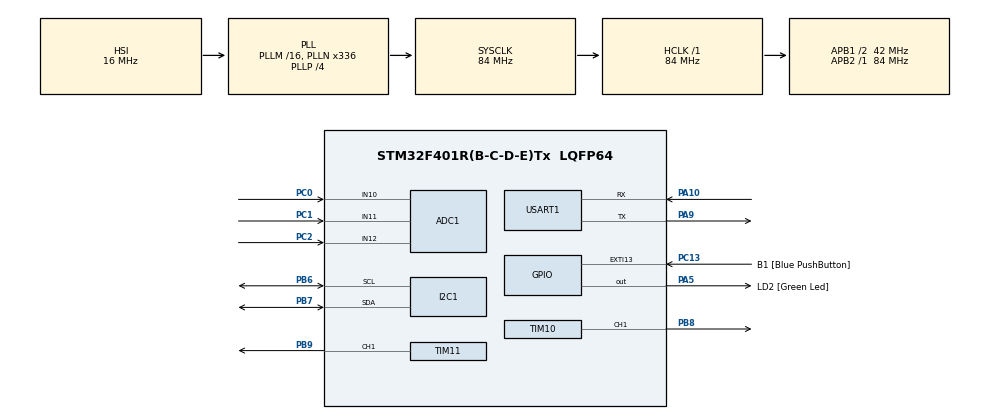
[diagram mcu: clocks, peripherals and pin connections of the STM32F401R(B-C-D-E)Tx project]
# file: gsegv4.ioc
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ADC1.Channel=ADC_CHANNEL_11
ADC1.Channel-0\#ChannelRegularConversion=ADC_CHANNEL_10
ADC1.Channel-1\#ChannelRegularConversion=ADC_CHANNEL_11
ADC1.Channel-2\#ChannelRegularConversion=ADC_CHANNEL_12
ADC1.ClockPrescaler=ADC_CLOCKPRESCALER_PCLK_DIV8
ADC1.ContinuousConvMode=ENABLE
ADC1.DMAContinuousRequests=ENABLE
ADC1.EOCSelection=EOC_SINGLE_CONV
ADC1.NbrOfConversion=3
ADC1.NbrOfConversionFlag=1
ADC1.Rank-1\#ChannelRegularConversion=2
ADC1.Rank-2\#ChannelRegularConversion=3
ADC1.ScanConvMode=ENABLE
ADC1.master=1
Dma.ADC1.0.Channel=DMA_CHANNEL_0
Dma.ADC1.0.Direction=DMA_PERIPH_TO_MEMORY
Dma.ADC1.0.FIFOMode=DMA_FIFOMODE_DISABLE
Dma.ADC1.0.Instance=DMA2_Stream0
Dma.ADC1.0.MemDataAlignment=DMA_MDATAALIGN_WORD
Dma.ADC1.0.MemInc=DMA_MINC_ENABLE
Dma.ADC1.0.Mode=DMA_CIRCULAR
Dma.ADC1.0.PeriphDataAlignment=DMA_PDATAALIGN_WORD
Dma.ADC1.0.PeriphInc=DMA_PINC_DISABLE
Dma.ADC1.0.Priority=DMA_PRIORITY_LOW
Dma.Request0=ADC1
FREERTOS.Tasks01=defaultTask,0,128,StartDefaultTask
Mcu.Family=STM32F4
Mcu.Name=STM32F401R(B-C-D-E)Tx
Mcu.Package=LQFP64
NVIC.PriorityGroup=NVIC_PRIORITYGROUP_4
NVIC.USART1_IRQn=true\:5\:0\:false
PA10.Mode=Asynchronous
PA10.Signal=USART1_RX
PA13.GPIO_Label=TMS
PA13.Mode=Trace-Asynchronous_SW
PA13.Signal=SYS_JTMS-SWDIO
PA14.GPIO_Label=TCK
PA14.Mode=Trace-Asynchronous_SW
PA14.Signal=SYS_JTCK-SWCLK
PA2.GPIO_Label=USART_TX
PA2.GPIO_Mode=GPIO_MODE_AF_PP
PA2.GPIO_PuPd=GPIO_NOPULL
PA2.GPIO_Speed=GPIO_SPEED_LOW
PA2.Signal=USART2_TX
PA3.GPIO_Label=USART_RX
PA3.GPIO_Mode=GPIO_MODE_AF_PP
PA3.GPIO_PuPd=GPIO_NOPULL
PA3.GPIO_Speed=GPIO_SPEED_LOW
PA3.Signal=USART2_RX
PA5.GPIO_Label=LD2 [Green Led]
PA5.GPIO_Mode=GPIO_MODE_OUTPUT_PP
PA5.GPIO_ModeDefaultOutputPP=GPIO_MODE_OUTPUT_PP
PA5.GPIO_PuPd=GPIO_NOPULL
PA5.GPIO_Speed=GPIO_SPEED_LOW
PA5.Signal=GPIO_Output
PA9.Mode=Asynchronous
PA9.Signal=USART1_TX
PB3.GPIO_Label=SWO
PB3.Mode=Trace-Asynchronous_SW
PB3.Signal=SYS_JTDO-SWO
PB6.Mode=I2C
PB6.Signal=I2C1_SCL
PB7.Mode=I2C
PB7.Signal=I2C1_SDA
PB8.Signal=S_TIM10_CH1
PB9.Signal=S_TIM11_CH1
PC0.Signal=ADCx_IN10
PC1.Signal=ADCx_IN11
PC13-ANTI_TAMP.GPIO_Label=B1 [Blue PushButton]
PC13-ANTI_TAMP.GPIO_ModeDefaultEXTI=GPIO_MODE_EVT_RISING
PC13-ANTI_TAMP.GPIO_PuPd=GPIO_NOPULL
PC13-ANTI_TAMP.Signal=GPXTI13
PC14-OSC32_IN.Signal=RCC_OSC32_IN
PC15-OSC32_OUT.Signal=RCC_OSC32_OUT
PC2.Signal=ADCx_IN12
PH0\ -\ OSC_IN.Signal=RCC_OSC_IN
PH1\ -\ OSC_OUT.Signal=RCC_OSC_OUT
ProjectManager.TargetToolchain=MDK-ARM 4.73
RCC.48MHZClocksFreq_Value=48000000
RCC.AHBFreq_Value=84000000
RCC.APB1CLKDivider=RCC_HCLK_DIV2
RCC.APB1Freq_Value=42000000
RCC.APB1TimFreq_Value=84000000
RCC.APB2Freq_Value=84000000
RCC.APB2TimFreq_Value=84000000
RCC.CortexFreq_Value=10500000
RCC.HCLKFreq_Value=84000000
RCC.HSE_VALUE=8000000
RCC.HSI_VALUE=16000000
RCC.LSE_VALUE=32768
RCC.PLLN=336
RCC.PLLP=RCC_PLLP_DIV4
RCC.PLLQ=7
RCC.SYSCLKFreq_VALUE=84000000
RCC.SYSCLKSource=RCC_SYSCLKSOURCE_PLLCLK
RCC.VCOOutputFreq_Value=336000000
SH.ADCx_IN10.0=ADC1_IN10,IN10
SH.ADCx_IN11.0=ADC1_IN11,IN11
SH.ADCx_IN12.0=ADC1_IN12,IN12
SH.S_TIM10_CH1.0=TIM10_CH1,PWM Generation1 CH1
SH.S_TIM11_CH1.0=TIM11_CH1,PWM Generation1 CH1
VP_FREERTOS_VS_ENABLE.Mode=Enabled
VP_TIM10_VS_ClockSourceINT.Mode=Enable_Timer
VP_TIM11_VS_ClockSourceINT.Mode=Enable_Timer

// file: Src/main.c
/**
  ******************************************************************************
  * File Name          : main.c
  * Date               : 25/04/2015 11:45:40
  * Description        : Main program body
  ******************************************************************************
  *
  * COPYRIGHT(c) 2015 STMicroelectronics
  *
  * Redistribution and use in source and binary forms, with or without modification,
  * are permitted provided that the following conditions are met:
  *   1. Redistributions of source code must retain the above copyright notice,
  *      this list of conditions and the following disclaimer.
  *   2. Redistributions in binary form must reproduce the above copyright notice,
  *      this list of conditions and the following disclaimer in the documentation
  *      and/or other materials provided with the distribution.
  *   3. Neither the name of STMicroelectronics nor the names of its contributors
  *      may be used to endorse or promote products derived from this software
  *      without specific prior written permission.
  *
  * THIS SOFTWARE IS PROVIDED BY THE COPYRIGHT HOLDERS AND CONTRIBUTORS "AS IS"
  * AND ANY EXPRESS OR IMPLIED WARRANTIES, INCLUDING, BUT NOT LIMITED TO, THE
  * IMPLIED WARRANTIES OF MERCHANTABILITY AND FITNESS FOR A PARTICULAR PURPOSE ARE
  * DISCLAIMED. IN NO EVENT SHALL THE COPYRIGHT HOLDER OR CONTRIBUTORS BE LIABLE
  * FOR ANY DIRECT, INDIRECT, INCIDENTAL, SPECIAL, EXEMPLARY, OR CONSEQUENTIAL
  * DAMAGES (INCLUDING, BUT NOT LIMITED TO, PROCUREMENT OF SUBSTITUTE GOODS OR
  * SERVICES; LOSS OF USE, DATA, OR PROFITS; OR BUSINESS INTERRUPTION) HOWEVER
  * CAUSED AND ON ANY THEORY OF LIABILITY, WHETHER IN CONTRACT, STRICT LIABILITY,
  * OR TORT (INCLUDING NEGLIGENCE OR OTHERWISE) ARISING IN ANY WAY OUT OF THE USE
  * OF THIS SOFTWARE, EVEN IF ADVISED OF THE POSSIBILITY OF SUCH DAMAGE.
  *
  ******************************************************************************
  */

#include "stdio.h"
#include "stm32f4xx_hal.h"
#include "cmsis_os.h"
#include "FreeRTOS.h"                       // Primary header for FreeRTOS
#include "task.h"                           // Header for FreeRTOS task functions
#include "queue.h"                          // FreeRTOS inter-task communication queues
#include "croutine.h"                       // Header for co-routines and such
#include "semphr.h"

#include "shares.h"
#include "task_safety.h"
#include "task_master.h"
#include "task_control.h"
#include "task_test.h"

ADC_HandleTypeDef hadc1;
DMA_HandleTypeDef hdma_adc1;

I2C_HandleTypeDef hi2c1;

TIM_HandleTypeDef htim10;
TIM_HandleTypeDef htim11;

UART_HandleTypeDef huart1;

void SystemClock_Config(void);
static void MX_GPIO_Init(void);
static void MX_DMA_Init(void);
static void MX_ADC1_Init(void);
static void MX_I2C1_Init(void);
static void MX_TIM10_Init(void);
static void MX_TIM11_Init(void);
static void MX_USART1_UART_Init(void);
void StartDefaultTask(void const * argument);
#ifdef __GNUC__
  /* With GCC/RAISONANCE, small printf (option LD Linker->Libraries->Small printf
     set to 'Yes') calls __io_putchar() */
  #define PUTCHAR_PROTOTYPE int __io_putchar(int ch)
#else
  #define PUTCHAR_PROTOTYPE int fputc(int ch, FILE *f)
#endif /* __GNUC__ */
PUTCHAR_PROTOTYPE
{
  /* Place your implementation of fputc here */
  /* e.g. write a character to the EVAL_COM1 and Loop until the end of transmission */
  HAL_UART_Transmit(&huart1, (uint8_t *)&ch, 1, 0xFFFF);

  return ch;
}

xQueueHandle update_coefficients_QUEUE;
xSemaphoreHandle testing_SEMAPHORE;
xSemaphoreHandle data_SEMAPHORE;
xQueueHandle control_sig_QUEUE;
//vSemaphoreCreateBinary(testing_SEMAPHORE);

int main(void)
{

  /* Reset of all peripherals, Initializes the Flash interface and the Systick. */
  HAL_Init();

  /* Configure the system clock */
  SystemClock_Config();

  /* Initialize all configured peripherals */
  MX_GPIO_Init();
  MX_DMA_Init();
  MX_ADC1_Init();
  MX_I2C1_Init();
  MX_TIM10_Init();
  MX_TIM11_Init();
  MX_USART1_UART_Init();

  xTaskCreate(task_safety, "Safety", 350, NULL, 1, NULL);
  xTaskCreate(task_master, "Master", 350, NULL, 1, NULL);
  xTaskCreate(task_control, "Control", 1000, NULL, 3, NULL);
  xTaskCreate(task_test, "Test", 500, NULL, 4, NULL);

  update_coefficients_QUEUE = xQueueCreate(3, sizeof(uint8_t));
  control_sig_QUEUE = xQueueCreate(3, sizeof(int16_t));;
  vSemaphoreCreateBinary(testing_SEMAPHORE);
  vSemaphoreCreateBinary(data_SEMAPHORE);
  osKernelStart();

  /* We should never get here as control is now taken by the scheduler */
  /* Infinite loop */
  while (1)
  {

  }

}

/** System Clock Configuration
*/
void SystemClock_Config(void)
{

  RCC_OscInitTypeDef RCC_OscInitStruct;
  RCC_ClkInitTypeDef RCC_ClkInitStruct;

  __PWR_CLK_ENABLE();

  __HAL_PWR_VOLTAGESCALING_CONFIG(PWR_REGULATOR_VOLTAGE_SCALE2);

  RCC_OscInitStruct.OscillatorType = RCC_OSCILLATORTYPE_HSI;
  RCC_OscInitStruct.HSIState = RCC_HSI_ON;
  RCC_OscInitStruct.HSICalibrationValue = 6;
  RCC_OscInitStruct.PLL.PLLState = RCC_PLL_ON;
  RCC_OscInitStruct.PLL.PLLSource = RCC_PLLSOURCE_HSI;
  RCC_OscInitStruct.PLL.PLLM = 16;
  RCC_OscInitStruct.PLL.PLLN = 336;
  RCC_OscInitStruct.PLL.PLLP = RCC_PLLP_DIV4;
  RCC_OscInitStruct.PLL.PLLQ = 7;
  HAL_RCC_OscConfig(&RCC_OscInitStruct);

  RCC_ClkInitStruct.ClockType = RCC_CLOCKTYPE_SYSCLK|RCC_CLOCKTYPE_PCLK1;
  RCC_ClkInitStruct.SYSCLKSource = RCC_SYSCLKSOURCE_PLLCLK;
  RCC_ClkInitStruct.AHBCLKDivider = RCC_SYSCLK_DIV1;
  RCC_ClkInitStruct.APB1CLKDivider = RCC_HCLK_DIV2;
  RCC_ClkInitStruct.APB2CLKDivider = RCC_HCLK_DIV1;
  HAL_RCC_ClockConfig(&RCC_ClkInitStruct, FLASH_LATENCY_2);

}

/* ADC1 init function */
void MX_ADC1_Init(void)
{

  ADC_ChannelConfTypeDef sConfig;

    /**Configure the global features of the ADC (Clock, Resolution, Data Alignment and number of conversion)
    */
  hadc1.Instance = ADC1;
  hadc1.Init.ClockPrescaler = ADC_CLOCKPRESCALER_PCLK_DIV8;
  hadc1.Init.Resolution = ADC_RESOLUTION12b;
  hadc1.Init.ScanConvMode = ENABLE;
  hadc1.Init.ContinuousConvMode = ENABLE;
  hadc1.Init.DiscontinuousConvMode = DISABLE;
  hadc1.Init.ExternalTrigConvEdge = ADC_EXTERNALTRIGCONVEDGE_NONE;
  hadc1.Init.DataAlign = ADC_DATAALIGN_RIGHT;
  hadc1.Init.NbrOfConversion = 3;
  hadc1.Init.DMAContinuousRequests = ENABLE;
  hadc1.Init.EOCSelection = EOC_SINGLE_CONV;
  HAL_ADC_Init(&hadc1);

    /**Configure for the selected ADC regular channel its corresponding rank in the sequencer and its sample time.
    */
  sConfig.Channel = ADC_CHANNEL_10;
  sConfig.Rank = 1;
  sConfig.SamplingTime = ADC_SAMPLETIME_3CYCLES;
  HAL_ADC_ConfigChannel(&hadc1, &sConfig);

    /**Configure for the selected ADC regular channel its corresponding rank in the sequencer and its sample time.
    */
  sConfig.Channel = ADC_CHANNEL_11;
  sConfig.Rank = 2;
  HAL_ADC_ConfigChannel(&hadc1, &sConfig);

    /**Configure for the selected ADC regular channel its corresponding rank in the sequencer and its sample time.
    */
  sConfig.Channel = ADC_CHANNEL_12;
  sConfig.Rank = 3;
  HAL_ADC_ConfigChannel(&hadc1, &sConfig);

}

/* I2C1 init function */
void MX_I2C1_Init(void)
{

  hi2c1.Instance = I2C1;
  hi2c1.Init.ClockSpeed = 100000;
  hi2c1.Init.DutyCycle = I2C_DUTYCYCLE_2;
  hi2c1.Init.OwnAddress1 = 0;
  hi2c1.Init.AddressingMode = I2C_ADDRESSINGMODE_7BIT;
  hi2c1.Init.DualAddressMode = I2C_DUALADDRESS_DISABLED;
  hi2c1.Init.OwnAddress2 = 0;
  hi2c1.Init.GeneralCallMode = I2C_GENERALCALL_DISABLED;
  hi2c1.Init.NoStretchMode = I2C_NOSTRETCH_DISABLED;
  HAL_I2C_Init(&hi2c1);

}

/* TIM10 init function */
void MX_TIM10_Init(void)
{

  TIM_OC_InitTypeDef sConfigOC;

  htim10.Instance = TIM10;
  htim10.Init.Prescaler = 0;
  htim10.Init.CounterMode = TIM_COUNTERMODE_UP;
  htim10.Init.Period = 10000;
  htim10.Init.ClockDivision = TIM_CLOCKDIVISION_DIV1;
  HAL_TIM_Base_Init(&htim10);

  HAL_TIM_PWM_Init(&htim10);

  sConfigOC.OCMode = TIM_OCMODE_PWM1;
  sConfigOC.Pulse = 0;
  sConfigOC.OCPolarity = TIM_OCPOLARITY_HIGH;
  sConfigOC.OCFastMode = TIM_OCFAST_DISABLE;
  HAL_TIM_PWM_ConfigChannel(&htim10, &sConfigOC, TIM_CHANNEL_1);
  HAL_TIM_PWM_Start(&htim10, TIM_CHANNEL_1);

}

/* TIM11 init function */
void MX_TIM11_Init(void)
{

  TIM_OC_InitTypeDef sConfigOC;

  htim11.Instance = TIM11;
  htim11.Init.Prescaler = 0;
  htim11.Init.CounterMode = TIM_COUNTERMODE_UP;
  htim11.Init.Period = 10000;
  htim11.Init.ClockDivision = TIM_CLOCKDIVISION_DIV1;
  HAL_TIM_Base_Init(&htim11);

  HAL_TIM_PWM_Init(&htim11);

  sConfigOC.OCMode = TIM_OCMODE_PWM1;
  sConfigOC.Pulse = 0;
  sConfigOC.OCPolarity = TIM_OCPOLARITY_HIGH;
  sConfigOC.OCFastMode = TIM_OCFAST_DISABLE;
  HAL_TIM_PWM_ConfigChannel(&htim11, &sConfigOC, TIM_CHANNEL_1);
  HAL_TIM_PWM_Start(&htim11, TIM_CHANNEL_1);
}

/* USART1 init function */
void MX_USART1_UART_Init(void)
{

  huart1.Instance = USART1;
  huart1.Init.BaudRate = 115200;
  huart1.Init.WordLength = UART_WORDLENGTH_8B;
  huart1.Init.StopBits = UART_STOPBITS_1;
  huart1.Init.Parity = UART_PARITY_NONE;
  huart1.Init.Mode = UART_MODE_TX_RX;
  huart1.Init.HwFlowCtl = UART_HWCONTROL_NONE;
  huart1.Init.OverSampling = UART_OVERSAMPLING_16;
  HAL_UART_Init(&huart1);

}

void MX_DMA_Init(void)
{
  /* DMA controller clock enable */
  __DMA2_CLK_ENABLE();

  /* DMA interrupt init */

}

/** Configure pins as
        * Analog
        * Input
        * Output
        * EVENT_OUT
        * EXTI
     PA2   ------> USART2_TX
     PA3   ------> USART2_RX
*/
void MX_GPIO_Init(void)
{

  GPIO_InitTypeDef GPIO_InitStruct;

  /* GPIO Ports Clock Enable */
  __GPIOC_CLK_ENABLE();
  __GPIOD_CLK_ENABLE();
  __GPIOH_CLK_ENABLE();
  __GPIOA_CLK_ENABLE();
  __GPIOB_CLK_ENABLE();

    /*Configure GPIO pins : PC9(ENCODER1B) */
    GPIO_InitStruct.Pin = GPIO_PIN_9;
    GPIO_InitStruct.Mode = GPIO_MODE_IT_RISING_FALLING;
    GPIO_InitStruct.Pull = GPIO_NOPULL;
    HAL_GPIO_Init(GPIOC, &GPIO_InitStruct);

    /*Configure GPIO pins : PA8(ENCODER1A) */
    GPIO_InitStruct.Pin = GPIO_PIN_8;
    GPIO_InitStruct.Mode = GPIO_MODE_IT_RISING_FALLING;
    GPIO_InitStruct.Pull = GPIO_NOPULL;
    HAL_GPIO_Init(GPIOA, &GPIO_InitStruct);

    HAL_NVIC_SetPriority(EXTI9_5_IRQn, 5, 0);
    HAL_NVIC_EnableIRQ(EXTI9_5_IRQn);

    /*Configure GPIO pins : PA11(ENCODER0B), PA12(ENCODER0A) */
    GPIO_InitStruct.Pin = GPIO_PIN_11|GPIO_PIN_12;
    GPIO_InitStruct.Mode = GPIO_MODE_IT_RISING_FALLING;
    GPIO_InitStruct.Pull = GPIO_NOPULL;
    HAL_GPIO_Init(GPIOA, &GPIO_InitStruct);
    HAL_NVIC_SetPriority(EXTI15_10_IRQn, 5, 0);
    HAL_NVIC_EnableIRQ(EXTI15_10_IRQn);

  /*Configure GPIO pin : PC13(EXTERNAL PUSHBUTTON) */
  GPIO_InitStruct.Pin = GPIO_PIN_13;
  GPIO_InitStruct.Mode = GPIO_MODE_EVT_RISING;
  GPIO_InitStruct.Pull = GPIO_NOPULL;
  HAL_GPIO_Init(GPIOC, &GPIO_InitStruct);

  /*Configure GPIO pins : PA2 PA3 (UART2 PINS) */
  GPIO_InitStruct.Pin = GPIO_PIN_2|GPIO_PIN_3;
  GPIO_InitStruct.Mode = GPIO_MODE_AF_PP;
  GPIO_InitStruct.Pull = GPIO_NOPULL;
  GPIO_InitStruct.Speed = GPIO_SPEED_LOW;
  GPIO_InitStruct.Alternate = GPIO_AF7_USART2;
  HAL_GPIO_Init(GPIOA, &GPIO_InitStruct);

  /*Configure GPIO pin : PA5(LED), PA15(M0INB) */
  GPIO_InitStruct.Pin = GPIO_PIN_5|GPIO_PIN_15;
  GPIO_InitStruct.Mode = GPIO_MODE_OUTPUT_PP;
  GPIO_InitStruct.Pull = GPIO_NOPULL;
  GPIO_InitStruct.Speed = GPIO_SPEED_LOW;
  HAL_GPIO_Init(GPIOA, &GPIO_InitStruct);

  /*Configure GPIO pins : PC10(M0ENAB) */
  GPIO_InitStruct.Pin = GPIO_PIN_10;
  GPIO_InitStruct.Mode = GPIO_MODE_INPUT;
  GPIO_InitStruct.Pull = GPIO_PULLUP;
  HAL_GPIO_Init(GPIOC, &GPIO_InitStruct);

  /*Configure GPIO pins : PC11(M0INA) */
  GPIO_InitStruct.Pin = GPIO_PIN_11;
  GPIO_InitStruct.Mode = GPIO_MODE_OUTPUT_PP;
  GPIO_InitStruct.Pull = GPIO_NOPULL;
  GPIO_InitStruct.Speed = GPIO_SPEED_LOW;
  HAL_GPIO_Init(GPIOC, &GPIO_InitStruct);

  /*Configure GPIO pins : PD2(M1INB) */
  GPIO_InitStruct.Pin = GPIO_PIN_2;
  GPIO_InitStruct.Mode = GPIO_MODE_OUTPUT_PP;
  GPIO_InitStruct.Pull = GPIO_NOPULL;
  GPIO_InitStruct.Speed = GPIO_SPEED_LOW;
  HAL_GPIO_Init(GPIOD, &GPIO_InitStruct);

  /*Configure GPIO pins : PB4(M1ENAB) */
  GPIO_InitStruct.Pin = GPIO_PIN_4;
  GPIO_InitStruct.Mode = GPIO_MODE_INPUT;
  GPIO_InitStruct.Pull = GPIO_PULLUP;
  HAL_GPIO_Init(GPIOB, &GPIO_InitStruct);

  /*Configure GPIO pins : PB5(M1INA) */
  GPIO_InitStruct.Pin = GPIO_PIN_5;
  GPIO_InitStruct.Mode = GPIO_MODE_OUTPUT_PP;
  GPIO_InitStruct.Pull = GPIO_NOPULL;
  GPIO_InitStruct.Speed = GPIO_SPEED_LOW;
  HAL_GPIO_Init(GPIOB, &GPIO_InitStruct);
}

/************************ (C) COPYRIGHT STMicroelectronics *****END OF FILE****/
